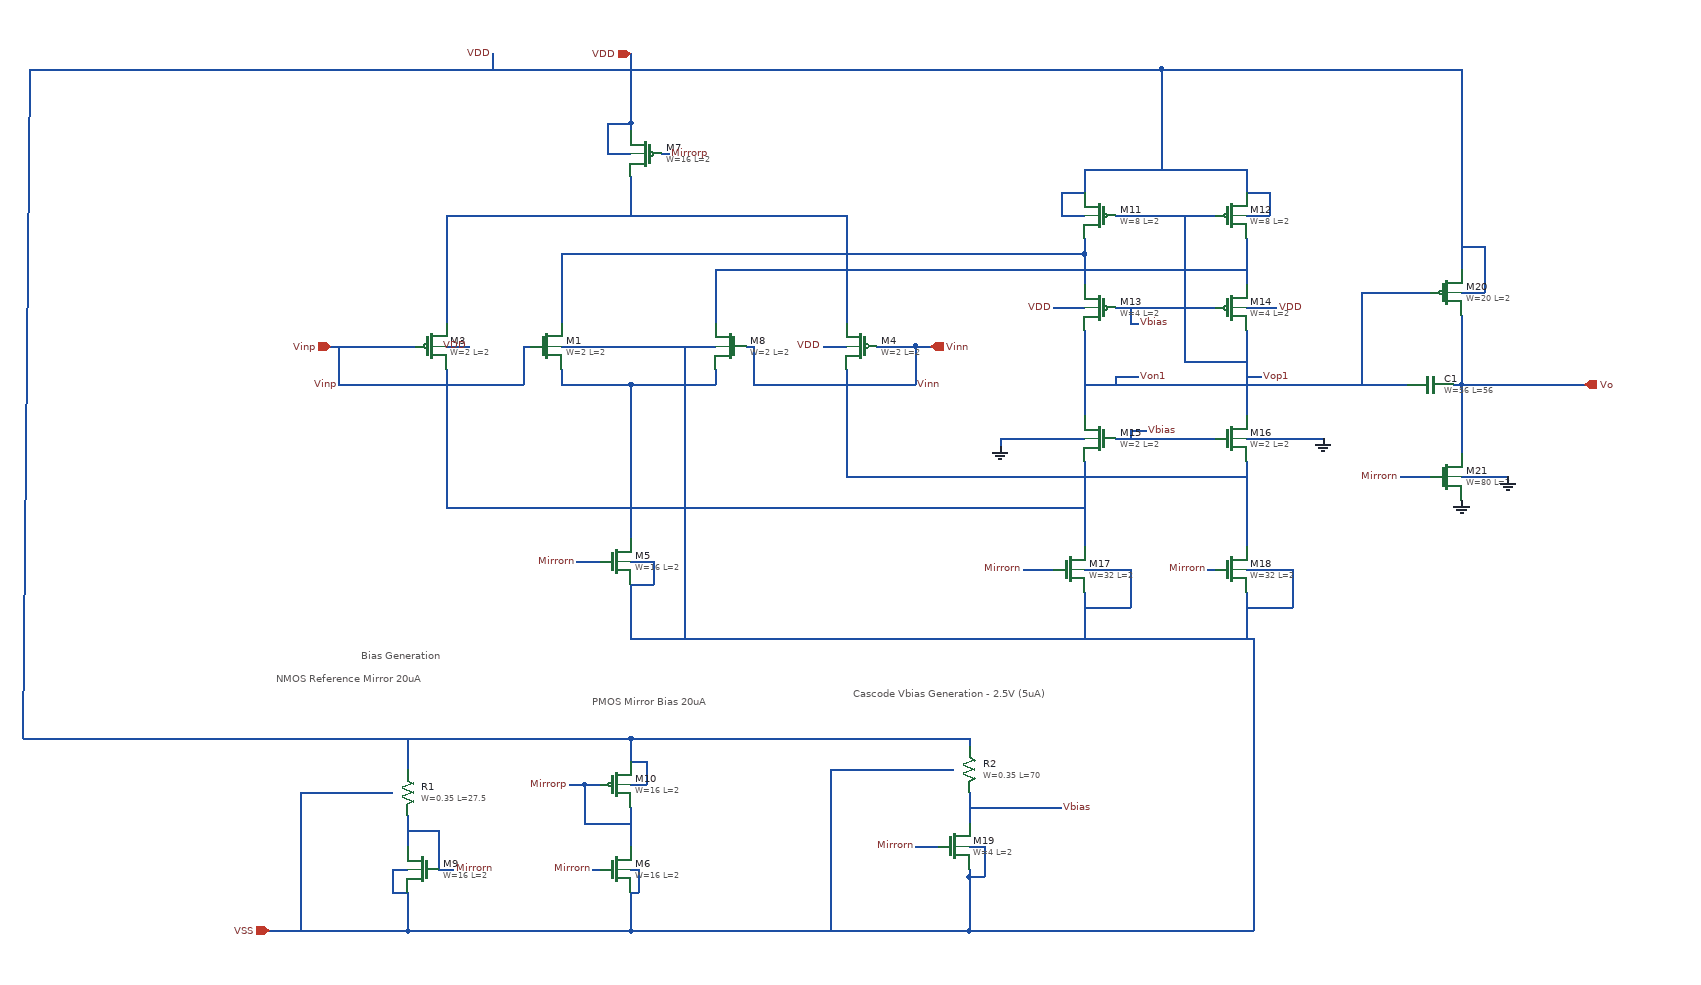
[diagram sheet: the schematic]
v {xschem version=3.4.4 file_version=1.2
}
G {}
K {}
V {}
S {}
E {}
T {Bias Generation} -310 410 0 0 0.4 0.4 {}
T {PMOS Mirror Bias 20uA} -10 470 0 0 0.4 0.4 {}
T {NMOS Reference Mirror 20uA} -420 440 0 0 0.4 0.4 {}
T {Cascode Vbias Generation - 2.5V (5uA)} 330 460 0 0 0.4 0.4 {}
N -50 20 -20 20 {
lab=GND}
N 100 20 150 20 {
lab=GND}
N 40 70 40 270 {
lab=#net1}
N -50 50 -50 70 {
lab=#net1}
N -50 70 40 70 {
lab=#net1}
N 40 70 150 70 {
lab=#net1}
N 150 50 150 70 {
lab=#net1}
N -250 730 -250 740 {
lab=GND}
N -270 700 -250 700 {
lab=GND}
N -270 700 -270 730 {
lab=GND}
N -270 730 -250 730 {
lab=GND}
N -250 630 -250 670 {
lab=Mirrorn}
N -210 650 -210 700 {
lab=Mirrorn}
N -250 650 -210 650 {
lab=Mirrorn}
N -210 700 -190 700 {
lab=Mirrorn}
N -320 600 -270 600 {
lab=GND}
N -250 560 -250 570 {
lab=VDD}
N 40 300 70 300 {
lab=GND}
N 70 300 70 330 {
lab=GND}
N 40 330 70 330 {
lab=GND}
N -30 300 0 300 {
lab=Mirrorn}
N -200 -150 -200 -10 {
lab=#net2}
N -200 -150 150 -150 {
lab=#net2}
N 320 -150 320 -10 {
lab=#net2}
N 150 -150 320 -150 {
lab=#net2}
N 40 -200 40 -150 {
lab=#net2}
N 40 -270 40 -260 {
lab=VDD}
N -200 20 -180 20 {
lab=VDD}
N -180 20 -170 20 {
lab=VDD}
N 290 20 320 20 {
lab=VDD}
N -270 20 -240 20 {
lab=Vinp}
N -10 700 0 700 {
lab=Mirrorn}
N 40 620 40 670 {
lab=Mirrorp}
N 40 700 50 700 {
lab=GND}
N 50 700 50 730 {
lab=GND}
N 40 730 50 730 {
lab=GND}
N 40 590 60 590 {
lab=VDD}
N 60 560 60 590 {
lab=VDD}
N 40 560 60 560 {
lab=VDD}
N 40 550 40 560 {
lab=VDD}
N -20 590 0 590 {
lab=Mirrorp}
N -20 590 -20 640 {
lab=Mirrorp}
N -20 640 40 640 {
lab=Mirrorp}
N -40 590 -20 590 {
lab=Mirrorp}
N 80 -230 90 -230 {
lab=Mirrorp}
N 670 -150 800 -150 {
lab=Vop1}
N 630 -210 630 -180 {
lab=VDD}
N 630 -210 840 -210 {
lab=VDD}
N 840 -210 840 -180 {
lab=VDD}
N 730 -280 730 -210 {
lab=VDD}
N 600 -150 630 -150 {
lab=VDD}
N 600 -180 600 -150 {
lab=VDD}
N 600 -180 630 -180 {
lab=VDD}
N 840 -150 870 -150 {
lab=VDD}
N 870 -180 870 -150 {
lab=VDD}
N 840 -180 870 -180 {
lab=VDD}
N -50 -100 -50 -10 {
lab=#net3}
N -50 -100 630 -100 {
lab=#net3}
N 630 -120 630 -100 {
lab=#net3}
N 630 -100 630 -60 {
lab=#net3}
N 150 -70 150 -10 {
lab=#net4}
N 150 -80 670 -80 {
lab=#net4}
N 670 -80 840 -80 {
lab=#net4}
N 840 -70 840 -60 {
lab=#net4}
N 840 -120 840 -70 {
lab=#net4}
N 670 -30 800 -30 {
lab=Vbias}
N 150 -80 150 -70 {
lab=#net4}
N 600 -30 630 -30 {
lab=VDD}
N 590 -30 600 -30 {
lab=VDD}
N 840 -30 880 -30 {
lab=VDD}
N 840 0 840 100 {
lab=Vop1}
N 630 -0 630 90 {
lab=Von1}
N 760 -150 760 40 {
lab=Vop1}
N 760 40 840 40 {
lab=Vop1}
N 630 90 630 110 {
lab=Von1}
N 840 100 840 110 {
lab=Vop1}
N 670 140 800 140 {
lab=Vbias}
N 520 140 520 150 {
lab=GND}
N 520 140 630 140 {
lab=GND}
N 840 140 940 140 {
lab=GND}
N 630 310 690 310 {
lab=GND}
N 840 310 900 310 {
lab=GND}
N 630 170 630 280 {
lab=#net5}
N 840 170 840 280 {
lab=#net6}
N 550 310 590 310 {
lab=Mirrorn}
N 790 310 800 310 {
lab=Mirrorn}
N 320 50 320 180 {
lab=#net6}
N 320 180 320 190 {
lab=#net6}
N 320 190 840 190 {
lab=#net6}
N -200 50 -200 210 {
lab=#net5}
N -200 210 -200 230 {
lab=#net5}
N -200 230 590 230 {
lab=#net5}
N 590 230 630 230 {
lab=#net5}
N 480 530 480 540 {
lab=VDD}
N 420 570 460 570 {
lab=GND}
N 480 600 480 630 {
lab=Vbias}
N 480 630 480 640 {
lab=Vbias}
N 480 710 480 730 {
lab=GND}
N 480 700 480 710 {
lab=GND}
N 480 670 500 670 {
lab=GND}
N 500 670 500 710 {
lab=GND}
N 480 710 500 710 {
lab=GND}
N 410 670 440 670 {
lab=Mirrorn}
N 480 620 600 620 {
lab=Vbias}
N 690 130 710 130 {
lab=Vbias}
N 690 130 690 140 {
lab=Vbias}
N 690 -10 700 -10 {
lab=Vbias}
N 690 -30 690 -10 {
lab=Vbias}
N 630 70 1050 70 {
lab=Von1}
N 990 -50 990 70 {
lab=Von1}
N 990 -50 1080 -50 {
lab=Von1}
N 1120 -20 1120 70 {
lab=Vo}
N 1110 70 1120 70 {
lab=Vo}
N 1120 70 1120 160 {
lab=Vo}
N 1120 190 1180 190 {
lab=GND}
N 1040 190 1080 190 {
lab=Mirrorn}
N 1120 70 1280 70 {
lab=Vo}
N 1120 -120 1120 -80 {
lab=VDD}
N 840 60 860 60 {
lab=Vop1}
N 670 60 670 70 {
lab=Von1}
N 670 60 700 60 {
lab=Von1}
N -100 20 -90 20 {
lab=Vinp}
N -350 20 -270 20 {
lab=Vinp}
N -100 20 -100 70 {
lab=Vinp}
N -340 70 -100 70 {
lab=Vinp}
N -340 30 -340 70 {
lab=Vinp}
N -340 20 -340 30 {
lab=Vinp}
N 360 20 410 20 {
lab=Vinn}
N 190 20 200 20 {
lab=Vinn}
N 200 20 200 70 {
lab=Vinn}
N 200 70 410 70 {
lab=Vinn}
N 410 20 410 70 {
lab=Vinn}
N 410 20 430 20 {
lab=Vinn}
N 40 -360 40 -270 {
lab=VDD}
N 40 -340 730 -340 {
lab=VDD}
N 730 -340 730 -280 {
lab=VDD}
N 730 -340 1120 -340 {
lab=VDD}
N 1120 -340 1120 -120 {
lab=VDD}
N -250 530 -250 560 {
lab=VDD}
N -250 530 40 530 {
lab=VDD}
N 40 530 40 550 {
lab=VDD}
N 40 530 480 530 {
lab=VDD}
N -750 530 -240 530 {
lab=VDD}
N -750 530 -740 -340 {
lab=VDD}
N -740 -340 40 -340 {
lab=VDD}
N -430 780 -380 780 {
lab=GND}
N -250 740 -250 780 {
lab=GND}
N -380 780 -250 780 {
lab=GND}
N -250 780 40 780 {
lab=GND}
N 40 740 40 780 {
lab=GND}
N 40 730 40 740 {
lab=GND}
N 40 780 480 780 {
lab=GND}
N 480 740 480 780 {
lab=GND}
N 480 730 480 740 {
lab=GND}
N -390 600 -390 780 {
lab=GND}
N -390 600 -320 600 {
lab=GND}
N 300 570 300 780 {
lab=GND}
N 300 570 420 570 {
lab=GND}
N 480 780 850 780 {
lab=GND}
N 850 400 850 780 {
lab=GND}
N 40 400 850 400 {
lab=GND}
N 40 340 40 400 {
lab=GND}
N 40 330 40 340 {
lab=GND}
N 630 340 630 400 {
lab=GND}
N 840 340 840 400 {
lab=GND}
N 900 310 900 360 {
lab=GND}
N 840 360 900 360 {
lab=GND}
N 690 310 690 360 {
lab=GND}
N 630 360 690 360 {
lab=GND}
N -20 20 100 20 {
lab=GND}
N 110 20 110 400 {
lab=GND}
N -140 -360 -140 -340 {
lab=VDD}
N 1120 -50 1150 -50 {
lab=VDD}
N 1150 -110 1150 -50 {
lab=VDD}
N 1120 -110 1150 -110 {
lab=VDD}
N 10 -230 40 -230 {
lab=VDD}
N 10 -270 10 -230 {
lab=VDD}
N 10 -270 40 -270 {
lab=VDD}
C {sky130_fd_pr/nfet_g5v0d10v5.sym} -70 20 0 0 {name=M1
W=2
L=2
nf=1
mult=1
ad="'int((nf+1)/2) * W/nf * 0.29'" 
pd="'2*int((nf+1)/2) * (W/nf + 0.29)'"
as="'int((nf+2)/2) * W/nf * 0.29'" 
ps="'2*int((nf+2)/2) * (W/nf + 0.29)'"
nrd="'0.29 / W'" nrs="'0.29 / W'"
sa=0 sb=0 sd=0
model=nfet_g5v0d10v5
spiceprefix=X
}
C {sky130_fd_pr/nfet_g5v0d10v5.sym} 20 300 0 0 {name=M5
W=16
L=2
nf=1
mult=1
ad="'int((nf+1)/2) * W/nf * 0.29'" 
pd="'2*int((nf+1)/2) * (W/nf + 0.29)'"
as="'int((nf+2)/2) * W/nf * 0.29'" 
ps="'2*int((nf+2)/2) * (W/nf + 0.29)'"
nrd="'0.29 / W'" nrs="'0.29 / W'"
sa=0 sb=0 sd=0
model=nfet_g5v0d10v5
spiceprefix=X
}
C {sky130_fd_pr/nfet_g5v0d10v5.sym} 170 20 0 1 {name=M8
W=2
L=2
nf=1
mult=1
ad="'int((nf+1)/2) * W/nf * 0.29'" 
pd="'2*int((nf+1)/2) * (W/nf + 0.29)'"
as="'int((nf+2)/2) * W/nf * 0.29'" 
ps="'2*int((nf+2)/2) * (W/nf + 0.29)'"
nrd="'0.29 / W'" nrs="'0.29 / W'"
sa=0 sb=0 sd=0
model=nfet_g5v0d10v5
spiceprefix=X
}
C {sky130_fd_pr/nfet_g5v0d10v5.sym} -230 700 0 1 {name=M9
W=16
L=2
nf=1
mult=1
ad="'int((nf+1)/2) * W/nf * 0.29'" 
pd="'2*int((nf+1)/2) * (W/nf + 0.29)'"
as="'int((nf+2)/2) * W/nf * 0.29'" 
ps="'2*int((nf+2)/2) * (W/nf + 0.29)'"
nrd="'0.29 / W'" nrs="'0.29 / W'"
sa=0 sb=0 sd=0
model=nfet_g5v0d10v5
spiceprefix=X
}
C {sky130_fd_pr/res_xhigh_po_0p35.sym} -250 600 0 0 {name=R1
W=0.35
L=27.5
model=res_xhigh_po_0p35
spiceprefix=X
 mult=1}
C {lab_pin.sym} -190 700 0 1 {name=p2 sig_type=std_logic lab=Mirrorn
}
C {sky130_fd_pr/pfet_g5v0d10v5.sym} 60 -230 0 1 {name=M7
W=16
L=2
nf=1
mult=1
ad="'int((nf+1)/2) * W/nf * 0.29'" 
pd="'2*int((nf+1)/2) * (W/nf + 0.29)'"
as="'int((nf+2)/2) * W/nf * 0.29'" 
ps="'2*int((nf+2)/2) * (W/nf + 0.29)'"
nrd="'0.29 / W'" nrs="'0.29 / W'"
sa=0 sb=0 sd=0
model=pfet_g5v0d10v5
spiceprefix=X
}
C {lab_pin.sym} -30 300 0 0 {name=p3 sig_type=std_logic lab=Mirrorn
}
C {sky130_fd_pr/pfet_g5v0d10v5.sym} -220 20 0 0 {name=M3
W=2
L=2
nf=1
mult=1
ad="'int((nf+1)/2) * W/nf * 0.29'" 
pd="'2*int((nf+1)/2) * (W/nf + 0.29)'"
as="'int((nf+2)/2) * W/nf * 0.29'" 
ps="'2*int((nf+2)/2) * (W/nf + 0.29)'"
nrd="'0.29 / W'" nrs="'0.29 / W'"
sa=0 sb=0 sd=0
model=pfet_g5v0d10v5
spiceprefix=X
}
C {sky130_fd_pr/pfet_g5v0d10v5.sym} 340 20 0 1 {name=M4
W=2
L=2
nf=1
mult=1
ad="'int((nf+1)/2) * W/nf * 0.29'" 
pd="'2*int((nf+1)/2) * (W/nf + 0.29)'"
as="'int((nf+2)/2) * W/nf * 0.29'" 
ps="'2*int((nf+2)/2) * (W/nf + 0.29)'"
nrd="'0.29 / W'" nrs="'0.29 / W'"
sa=0 sb=0 sd=0
model=pfet_g5v0d10v5
spiceprefix=X
}
C {lab_pin.sym} -170 20 1 0 {name=p5 sig_type=std_logic lab=VDD
}
C {lab_pin.sym} 290 20 1 0 {name=p6 sig_type=std_logic lab=VDD
}
C {sky130_fd_pr/nfet_g5v0d10v5.sym} 20 700 0 0 {name=M6
W=16
L=2
nf=1
mult=1
ad="'int((nf+1)/2) * W/nf * 0.29'" 
pd="'2*int((nf+1)/2) * (W/nf + 0.29)'"
as="'int((nf+2)/2) * W/nf * 0.29'" 
ps="'2*int((nf+2)/2) * (W/nf + 0.29)'"
nrd="'0.29 / W'" nrs="'0.29 / W'"
sa=0 sb=0 sd=0
model=nfet_g5v0d10v5
spiceprefix=X
}
C {sky130_fd_pr/pfet_g5v0d10v5.sym} 20 590 0 0 {name=M10
W=16
L=2
nf=1
mult=1
ad="'int((nf+1)/2) * W/nf * 0.29'" 
pd="'2*int((nf+1)/2) * (W/nf + 0.29)'"
as="'int((nf+2)/2) * W/nf * 0.29'" 
ps="'2*int((nf+2)/2) * (W/nf + 0.29)'"
nrd="'0.29 / W'" nrs="'0.29 / W'"
sa=0 sb=0 sd=0
model=pfet_g5v0d10v5
spiceprefix=X
}
C {lab_pin.sym} -10 700 0 0 {name=p11 sig_type=std_logic lab=Mirrorn
}
C {lab_pin.sym} 90 -230 0 1 {name=p13 sig_type=std_logic lab=Mirrorp
}
C {lab_pin.sym} -40 590 0 0 {name=p14 sig_type=std_logic lab=Mirrorp
}
C {sky130_fd_pr/pfet_g5v0d10v5.sym} 650 -150 0 1 {name=M11
W=8
L=2
nf=1
mult=1
ad="'int((nf+1)/2) * W/nf * 0.29'" 
pd="'2*int((nf+1)/2) * (W/nf + 0.29)'"
as="'int((nf+2)/2) * W/nf * 0.29'" 
ps="'2*int((nf+2)/2) * (W/nf + 0.29)'"
nrd="'0.29 / W'" nrs="'0.29 / W'"
sa=0 sb=0 sd=0
model=pfet_g5v0d10v5
spiceprefix=X
}
C {sky130_fd_pr/pfet_g5v0d10v5.sym} 820 -150 0 0 {name=M12
W=8
L=2
nf=1
mult=1
ad="'int((nf+1)/2) * W/nf * 0.29'" 
pd="'2*int((nf+1)/2) * (W/nf + 0.29)'"
as="'int((nf+2)/2) * W/nf * 0.29'" 
ps="'2*int((nf+2)/2) * (W/nf + 0.29)'"
nrd="'0.29 / W'" nrs="'0.29 / W'"
sa=0 sb=0 sd=0
model=pfet_g5v0d10v5
spiceprefix=X
}
C {sky130_fd_pr/pfet_g5v0d10v5.sym} 650 -30 0 1 {name=M13
W=4
L=2
nf=1
mult=1
ad="'int((nf+1)/2) * W/nf * 0.29'" 
pd="'2*int((nf+1)/2) * (W/nf + 0.29)'"
as="'int((nf+2)/2) * W/nf * 0.29'" 
ps="'2*int((nf+2)/2) * (W/nf + 0.29)'"
nrd="'0.29 / W'" nrs="'0.29 / W'"
sa=0 sb=0 sd=0
model=pfet_g5v0d10v5
spiceprefix=X
}
C {sky130_fd_pr/pfet_g5v0d10v5.sym} 820 -30 0 0 {name=M14
W=4
L=2
nf=1
mult=1
ad="'int((nf+1)/2) * W/nf * 0.29'" 
pd="'2*int((nf+1)/2) * (W/nf + 0.29)'"
as="'int((nf+2)/2) * W/nf * 0.29'" 
ps="'2*int((nf+2)/2) * (W/nf + 0.29)'"
nrd="'0.29 / W'" nrs="'0.29 / W'"
sa=0 sb=0 sd=0
model=pfet_g5v0d10v5
spiceprefix=X
}
C {lab_pin.sym} 590 -30 0 0 {name=p16 sig_type=std_logic lab=VDD
}
C {lab_pin.sym} 880 -30 0 1 {name=p17 sig_type=std_logic lab=VDD
}
C {sky130_fd_pr/nfet_g5v0d10v5.sym} 650 140 0 1 {name=M15
W=2
L=2
nf=1
mult=1
ad="'int((nf+1)/2) * W/nf * 0.29'" 
pd="'2*int((nf+1)/2) * (W/nf + 0.29)'"
as="'int((nf+2)/2) * W/nf * 0.29'" 
ps="'2*int((nf+2)/2) * (W/nf + 0.29)'"
nrd="'0.29 / W'" nrs="'0.29 / W'"
sa=0 sb=0 sd=0
model=nfet_g5v0d10v5
spiceprefix=X
}
C {sky130_fd_pr/nfet_g5v0d10v5.sym} 820 140 0 0 {name=M16
W=2
L=2
nf=1
mult=1
ad="'int((nf+1)/2) * W/nf * 0.29'" 
pd="'2*int((nf+1)/2) * (W/nf + 0.29)'"
as="'int((nf+2)/2) * W/nf * 0.29'" 
ps="'2*int((nf+2)/2) * (W/nf + 0.29)'"
nrd="'0.29 / W'" nrs="'0.29 / W'"
sa=0 sb=0 sd=0
model=nfet_g5v0d10v5
spiceprefix=X
}
C {gnd.sym} 520 150 0 0 {name=l7 lab=GND}
C {gnd.sym} 940 140 0 0 {name=l8 lab=GND}
C {sky130_fd_pr/nfet_g5v0d10v5.sym} 610 310 0 0 {name=M17
W=32
L=2
nf=1
mult=1
ad="'int((nf+1)/2) * W/nf * 0.29'" 
pd="'2*int((nf+1)/2) * (W/nf + 0.29)'"
as="'int((nf+2)/2) * W/nf * 0.29'" 
ps="'2*int((nf+2)/2) * (W/nf + 0.29)'"
nrd="'0.29 / W'" nrs="'0.29 / W'"
sa=0 sb=0 sd=0
model=nfet_g5v0d10v5
spiceprefix=X
}
C {sky130_fd_pr/nfet_g5v0d10v5.sym} 820 310 0 0 {name=M18
W=32
L=2
nf=1
mult=1
ad="'int((nf+1)/2) * W/nf * 0.29'" 
pd="'2*int((nf+1)/2) * (W/nf + 0.29)'"
as="'int((nf+2)/2) * W/nf * 0.29'" 
ps="'2*int((nf+2)/2) * (W/nf + 0.29)'"
nrd="'0.29 / W'" nrs="'0.29 / W'"
sa=0 sb=0 sd=0
model=nfet_g5v0d10v5
spiceprefix=X
}
C {lab_pin.sym} 550 310 0 0 {name=p18 sig_type=std_logic lab=Mirrorn
}
C {lab_pin.sym} 790 310 0 0 {name=p19 sig_type=std_logic lab=Mirrorn
}
C {sky130_fd_pr/res_xhigh_po_0p35.sym} 480 570 0 0 {name=R2
W=0.35
L=70
model=res_xhigh_po_0p35
spiceprefix=X
 mult=1}
C {sky130_fd_pr/nfet_g5v0d10v5.sym} 460 670 0 0 {name=M19
W=4
L=2
nf=1
mult=1
ad="'int((nf+1)/2) * W/nf * 0.29'" 
pd="'2*int((nf+1)/2) * (W/nf + 0.29)'"
as="'int((nf+2)/2) * W/nf * 0.29'" 
ps="'2*int((nf+2)/2) * (W/nf + 0.29)'"
nrd="'0.29 / W'" nrs="'0.29 / W'"
sa=0 sb=0 sd=0
model=nfet_g5v0d10v5
spiceprefix=X
}
C {lab_pin.sym} 410 670 0 0 {name=p21 sig_type=std_logic lab=Mirrorn
}
C {lab_pin.sym} 600 620 0 1 {name=p22 sig_type=std_logic lab=Vbias
}
C {lab_pin.sym} 710 130 0 1 {name=p23 sig_type=std_logic lab=Vbias
}
C {lab_pin.sym} 700 -10 0 1 {name=p24 sig_type=std_logic lab=Vbias
}
C {sky130_fd_pr/pfet_g5v0d10v5.sym} 1100 -50 0 0 {name=M20
W=20
L=2
nf=1
mult=1
ad="'int((nf+1)/2) * W/nf * 0.29'" 
pd="'2*int((nf+1)/2) * (W/nf + 0.29)'"
as="'int((nf+2)/2) * W/nf * 0.29'" 
ps="'2*int((nf+2)/2) * (W/nf + 0.29)'"
nrd="'0.29 / W'" nrs="'0.29 / W'"
sa=0 sb=0 sd=0
model=pfet_g5v0d10v5
spiceprefix=X
}
C {sky130_fd_pr/cap_mim_m3_1.sym} 1080 70 3 0 {name=C1 model=cap_mim_m3_1 W=56 L=56 MF=1 spiceprefix=X}
C {sky130_fd_pr/nfet_g5v0d10v5.sym} 1100 190 0 0 {name=M21
W=80
L=2
nf=1
mult=1
ad="'int((nf+1)/2) * W/nf * 0.29'" 
pd="'2*int((nf+1)/2) * (W/nf + 0.29)'"
as="'int((nf+2)/2) * W/nf * 0.29'" 
ps="'2*int((nf+2)/2) * (W/nf + 0.29)'"
nrd="'0.29 / W'" nrs="'0.29 / W'"
sa=0 sb=0 sd=0
model=nfet_g5v0d10v5
spiceprefix=X
}
C {gnd.sym} 1120 220 0 0 {name=l15 lab=GND}
C {gnd.sym} 1180 190 3 0 {name=l16 lab=GND}
C {lab_pin.sym} 1040 190 0 0 {name=p25 sig_type=std_logic lab=Mirrorn
}
C {lab_pin.sym} 860 60 0 1 {name=p28 sig_type=std_logic lab=Vop1}
C {lab_pin.sym} 700 60 0 1 {name=p29 sig_type=std_logic lab=Von1}
C {ipin.sym} -350 20 0 0 {name=p30 lab=Vinp}
C {ipin.sym} 430 20 0 1 {name=p7 lab=Vinn}
C {opin.sym} 1280 70 0 0 {name=p8 lab=Vo}
C {iopin.sym} 40 -360 3 0 {name=p9 lab=VDD}
C {lab_pin.sym} -140 -360 1 0 {name=p4 sig_type=std_logic lab=VDD
}
C {lab_pin.sym} -340 70 0 0 {name=p20 sig_type=std_logic lab=Vinp}
C {lab_pin.sym} 410 70 0 1 {name=p26 sig_type=std_logic lab=Vinn}
C {iopin.sym} -430 780 2 0 {name=p12 lab=VSS}

